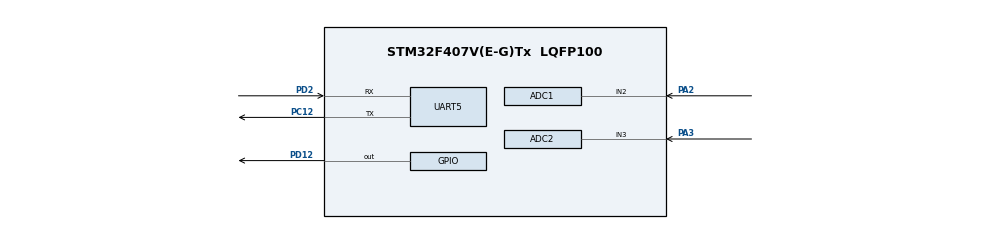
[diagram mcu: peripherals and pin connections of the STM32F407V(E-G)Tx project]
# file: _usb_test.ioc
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ADC1.Channel-8\#ChannelRegularConversion=ADC_CHANNEL_2
ADC1.ClockPrescaler=ADC_CLOCK_SYNC_PCLK_DIV8
ADC1.ContinuousConvMode=ENABLE
ADC1.DMAContinuousRequests=ENABLE
ADC1.EOCSelection=ADC_EOC_SINGLE_CONV
ADC1.Mode=ADC_DUALMODE_REGSIMULT
ADC1.NbrOfConversionFlag=1
ADC1.Rank-8\#ChannelRegularConversion=1
ADC1.SamplingTime-8\#ChannelRegularConversion=ADC_SAMPLETIME_3CYCLES
ADC1.master=1
ADC2.Channel-1\#ChannelRegularConversion=ADC_CHANNEL_3
ADC2.ClockPrescaler=ADC_CLOCK_SYNC_PCLK_DIV8
ADC2.DMAAccessMode=ADC_DMAACCESSMODE_2
ADC2.Mode=ADC_DUALMODE_REGSIMULT
ADC2.NbrOfConversionFlag=1
ADC2.Rank-1\#ChannelRegularConversion=1
ADC2.SamplingTime-1\#ChannelRegularConversion=ADC_SAMPLETIME_3CYCLES
Dma.ADC1.0.Direction=DMA_PERIPH_TO_MEMORY
Dma.ADC1.0.FIFOMode=DMA_FIFOMODE_DISABLE
Dma.ADC1.0.Instance=DMA2_Stream0
Dma.ADC1.0.MemDataAlignment=DMA_MDATAALIGN_WORD
Dma.ADC1.0.MemInc=DMA_MINC_ENABLE
Dma.ADC1.0.Mode=DMA_CIRCULAR
Dma.ADC1.0.PeriphDataAlignment=DMA_PDATAALIGN_WORD
Dma.ADC1.0.PeriphInc=DMA_PINC_DISABLE
Dma.ADC1.0.Priority=DMA_PRIORITY_LOW
Dma.Request0=ADC1
Mcu.Family=STM32F4
Mcu.Name=STM32F407V(E-G)Tx
Mcu.Package=LQFP100
NVIC.DMA2_Stream0_IRQn=true\:0\:0\:false\:false\:true\:false\:true\:true
NVIC.PriorityGroup=NVIC_PRIORITYGROUP_0
PA2.Signal=ADCx_IN2
PA3.Signal=ADCx_IN3
PC12.Mode=Asynchronous
PC12.Signal=UART5_TX
PC14-OSC32_IN.Mode=LSE-External-Oscillator
PC14-OSC32_IN.Signal=RCC_OSC32_IN
PC15-OSC32_OUT.Mode=LSE-External-Oscillator
PC15-OSC32_OUT.Signal=RCC_OSC32_OUT
PD12.GPIO_Speed=GPIO_SPEED_FREQ_VERY_HIGH
PD12.Signal=GPIO_Output
PD2.Mode=Asynchronous
PD2.Signal=UART5_RX
PH0-OSC_IN.Mode=HSE-External-Oscillator
PH0-OSC_IN.Signal=RCC_OSC_IN
PH1-OSC_OUT.Mode=HSE-External-Oscillator
PH1-OSC_OUT.Signal=RCC_OSC_OUT
ProjectManager.HeapSize=0x200
ProjectManager.StackSize=0x400
ProjectManager.TargetToolchain=STM32CubeIDE
RCC.48MHZClocksFreq_Value=96000000
RCC.AHBFreq_Value=336000000
RCC.APB1CLKDivider=RCC_HCLK_DIV4
RCC.APB1Freq_Value=84000000
RCC.APB1TimFreq_Value=168000000
RCC.APB2CLKDivider=RCC_HCLK_DIV2
RCC.APB2Freq_Value=168000000
RCC.APB2TimFreq_Value=336000000
RCC.CortexFreq_Value=336000000
RCC.HCLKFreq_Value=336000000
RCC.HSE_VALUE=8000000
RCC.HSI_VALUE=16000000
RCC.PLLM=2
RCC.PLLN=168
RCC.PLLQ=7
RCC.PLLSourceVirtual=RCC_PLLSOURCE_HSE
RCC.SYSCLKFreq_VALUE=336000000
RCC.SYSCLKSource=RCC_SYSCLKSOURCE_PLLCLK
RCC.VCOOutputFreq_Value=672000000
SH.ADCx_IN2.0=ADC1_IN2,IN2
SH.ADCx_IN3.0=ADC2_IN3,IN3
TIM2.Period=0xFFFFFFFF
TIM2.Prescaler=167
UART5.VirtualMode=Asynchronous
VP_TIM2_VS_OPM.Mode=OPM_bit
board=STM32F407G-DISC1

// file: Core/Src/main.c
/* USER CODE BEGIN Header */
/**
  ******************************************************************************
  * @file           : main.c
  * @brief          : Main program body
  ******************************************************************************
  * @attention
  *
  * Copyright (c) 2025 STMicroelectronics.
  * All rights reserved.
  *
  * This software is licensed under terms that can be found in the LICENSE file
  * in the root directory of this software component.
  * If no LICENSE file comes with this software, it is provided AS-IS.
  *
  ******************************************************************************
  */
/* USER CODE END Header */
#include "main.h"

/* USER CODE BEGIN Includes */
#include <stdio.h>
#include <string.h>
uint8_t mode,mode_ex;
uint8_t rxdata;
uint8_t completed=0;
/* USER CODE END Includes */

ADC_HandleTypeDef hadc1;
ADC_HandleTypeDef hadc2;
DMA_HandleTypeDef hdma_adc1;

TIM_HandleTypeDef htim2;

UART_HandleTypeDef huart5;

/* USER CODE BEGIN PV */
char buffer_cokomel[3]="ABC";
uint16_t adc_buffer_1[4096],adc_buffer_2[4096];
uint16_t adc_buffer[4096];
uint32_t adc_buffer_ex[4096];
void HAL_ADC_ConvHalfCpltCallback(ADC_HandleTypeDef* hadc){

}

void HAL_ADC_ConvCpltCallback(ADC_HandleTypeDef *hadc){
	//uint16_t ts_cal1=*TEMPSENSOR_CAL1_ADDR;
	//uint16_t ts_cal2=*TEMPSENSOR_CAL2_ADDR;
	//float temperature = ((float)(110-30)/(ts_cal2-ts_cal1)) * (adc_buffer[0] - ts_cal1)  + 30;
	HAL_GPIO_TogglePin(GPIOD, GPIO_PIN_12);
	//HAL_UART_Transmit(&huart4, buffer_cokomel,3,100);
	//HAL_ADC_Stop_DMA(&hadc2);
	//CDC_Transmit_FS(adc_buffer,sizeof(adc_buffer));
	//sprintf(buffer_cokomel, "%d", temperature);
	// do stuff with result
	//HAL_UART_Transmit(&huart4, buffer_cokomel,3,100);

//

}
/* USER CODE END PV */

void SystemClock_Config(void);
static void MX_GPIO_Init(void);
static void MX_DMA_Init(void);
static void MX_ADC1_Init(void);
static void MX_TIM2_Init(void);
static void MX_ADC2_Init(void);
static void MX_UART5_Init(void);

int main(void)
{

  /* MCU Configuration--------------------------------------------------------*/

  /* Reset of all peripherals, Initializes the Flash interface and the Systick. */
  HAL_Init();

  /* Configure the system clock */
  SystemClock_Config();

  /* Initialize all configured peripherals */
  MX_GPIO_Init();
  MX_DMA_Init();
  MX_ADC1_Init();
  MX_TIM2_Init();
  MX_ADC2_Init();
  MX_UART5_Init();

  /* Infinite loop */
  /* USER CODE BEGIN WHILE */
  //HAL_ADC_Start_DMA(&hadc1,(uint32_t *)adc_buffer,sizeof(adc_buffer));
  HAL_ADC_Start(&hadc2);
  HAL_ADCEx_MultiModeStart_DMA(&hadc1, adc_buffer_ex, sizeof(adc_buffer_ex));

   while (1)
  {
	  HAL_UART_Receive(&huart5, &rxdata,1,1);
	  if(rxdata=='a'){
		  HAL_ADC_Stop(&hadc2);
		  HAL_ADCEx_MultiModeStop_DMA(&hadc1);
			  if(HAL_UART_Transmit(&huart5, adc_buffer_ex,sizeof(adc_buffer_ex),2000)!=HAL_OK)
			  HAL_UART_Transmit(&huart5, buffer_cokomel,3,100);
		  rxdata='\0';
		  HAL_ADC_Start(&hadc2);
		  HAL_ADCEx_MultiModeStart_DMA(&hadc1, adc_buffer_ex, sizeof(adc_buffer_ex));

		//  HAL_ADC_Start_DMA(&hadc1,(uint32_t *)adc_buffer,sizeof(adc_buffer));
		  completed=0;
		/*  HAL_ADC_Start(&hadc2);
		  HAL_ADCEx_MultiModeStart_DMA(&hadc1,(uint32_t *)adc_buffer,sizeof(adc_buffer));
		//  HAL_ADC_Start_DMA(&hadc2,(uint32_t *)&adc_buffer[4096],8192);
		  rxdata='\0';
		  HAL_Delay(100);
		  HAL_ADCEx_MultiModeStop_DMA(&hadc1);
		  HAL_ADC_Stop(&hadc2);
		  //HAL_ADC_Stop_DMA(&hadc2);
		  CDC_Transmit_FS(adc_buffer,sizeof(adc_buffer));
		 // CDC_Transmit_FS(adc_buffer_2,sizeof(adc_buffer_2));
*/
	  }

	//  HAL_Delay(1);

    /* USER CODE END WHILE */

  }
}

void SystemClock_Config1(void)
{
  RCC_OscInitTypeDef RCC_OscInitStruct = {0};
  RCC_ClkInitTypeDef RCC_ClkInitStruct = {0};

  /** Configure the main internal regulator output voltage
  */
  __HAL_RCC_PWR_CLK_ENABLE();
  __HAL_PWR_VOLTAGESCALING_CONFIG(PWR_REGULATOR_VOLTAGE_SCALE1);

  /** Initializes the RCC Oscillators according to the specified parameters
  * in the RCC_OscInitTypeDef structure.
  */
  RCC_OscInitStruct.OscillatorType = RCC_OSCILLATORTYPE_HSE;
  RCC_OscInitStruct.HSEState = RCC_HSE_ON;
  RCC_OscInitStruct.PLL.PLLState = RCC_PLL_ON;
  RCC_OscInitStruct.PLL.PLLSource = RCC_PLLSOURCE_HSE;
  RCC_OscInitStruct.PLL.PLLM = 4;
  RCC_OscInitStruct.PLL.PLLN = 180;
  RCC_OscInitStruct.PLL.PLLP = RCC_PLLP_DIV2;
  RCC_OscInitStruct.PLL.PLLQ = 7;
  if (HAL_RCC_OscConfig(&RCC_OscInitStruct) != HAL_OK)
  {
    Error_Handler();
  }

  /** Initializes the CPU, AHB and APB buses clocks
  */
  RCC_ClkInitStruct.ClockType = RCC_CLOCKTYPE_HCLK|RCC_CLOCKTYPE_SYSCLK
                              |RCC_CLOCKTYPE_PCLK1|RCC_CLOCKTYPE_PCLK2;
  RCC_ClkInitStruct.SYSCLKSource = RCC_SYSCLKSOURCE_PLLCLK;
  RCC_ClkInitStruct.AHBCLKDivider = RCC_SYSCLK_DIV1;
  RCC_ClkInitStruct.APB1CLKDivider = RCC_HCLK_DIV16;
  RCC_ClkInitStruct.APB2CLKDivider = RCC_HCLK_DIV1;

  if (HAL_RCC_ClockConfig(&RCC_ClkInitStruct, FLASH_LATENCY_5) != HAL_OK)
  {
    Error_Handler();
  }
}
void SystemClock_Config(void)
{
  RCC_OscInitTypeDef RCC_OscInitStruct = {0};
  RCC_ClkInitTypeDef RCC_ClkInitStruct = {0};

  /** Configure the main internal regulator output voltage
  */
  __HAL_RCC_PWR_CLK_ENABLE();
  __HAL_PWR_VOLTAGESCALING_CONFIG(PWR_REGULATOR_VOLTAGE_SCALE1);

  /** Initializes the RCC Oscillators according to the specified parameters
  * in the RCC_OscInitTypeDef structure.
  */
  RCC_OscInitStruct.OscillatorType = RCC_OSCILLATORTYPE_HSE;
  RCC_OscInitStruct.HSEState = RCC_HSE_ON;
  RCC_OscInitStruct.PLL.PLLState = RCC_PLL_ON;
  RCC_OscInitStruct.PLL.PLLSource = RCC_PLLSOURCE_HSE;
  RCC_OscInitStruct.PLL.PLLM = 4;
  RCC_OscInitStruct.PLL.PLLN = 180;
  RCC_OscInitStruct.PLL.PLLP = RCC_PLLP_DIV2;
  RCC_OscInitStruct.PLL.PLLQ = 7;
  if (HAL_RCC_OscConfig(&RCC_OscInitStruct) != HAL_OK)
  {
    Error_Handler();
  }

  /** Initializes the CPU, AHB and APB buses clocks
  */
  RCC_ClkInitStruct.ClockType = RCC_CLOCKTYPE_HCLK|RCC_CLOCKTYPE_SYSCLK
                              |RCC_CLOCKTYPE_PCLK1|RCC_CLOCKTYPE_PCLK2;
  RCC_ClkInitStruct.SYSCLKSource = RCC_SYSCLKSOURCE_PLLCLK;
  RCC_ClkInitStruct.AHBCLKDivider = RCC_SYSCLK_DIV1;
  RCC_ClkInitStruct.APB1CLKDivider = RCC_HCLK_DIV16;
  RCC_ClkInitStruct.APB2CLKDivider = RCC_HCLK_DIV1;

  if (HAL_RCC_ClockConfig(&RCC_ClkInitStruct, FLASH_LATENCY_5) != HAL_OK)
  {
    Error_Handler();
  }
}

static void MX_ADC1_Init(void)
{

  ADC_MultiModeTypeDef multimode = {0};
  ADC_ChannelConfTypeDef sConfig = {0};

  /** Configure the global features of the ADC (Clock, Resolution, Data Alignment and number of conversion)
  */
  hadc1.Instance = ADC1;
  hadc1.Init.ClockPrescaler = ADC_CLOCK_SYNC_PCLK_DIV2;
  hadc1.Init.Resolution = ADC_RESOLUTION_12B;
  hadc1.Init.ScanConvMode = DISABLE;
  hadc1.Init.ContinuousConvMode = ENABLE;
  hadc1.Init.DiscontinuousConvMode = DISABLE;
  hadc1.Init.ExternalTrigConvEdge = ADC_EXTERNALTRIGCONVEDGE_NONE;
  hadc1.Init.ExternalTrigConv = ADC_SOFTWARE_START;
  hadc1.Init.DataAlign = ADC_DATAALIGN_RIGHT;
  hadc1.Init.NbrOfConversion = 1;
  hadc1.Init.DMAContinuousRequests = ENABLE;
  hadc1.Init.EOCSelection = ADC_EOC_SINGLE_CONV;
  if (HAL_ADC_Init(&hadc1) != HAL_OK)
  {
    Error_Handler();
  }

  /** Configure the ADC multi-mode
  */
  multimode.Mode = ADC_DUALMODE_REGSIMULT;
  multimode.DMAAccessMode = ADC_DMAACCESSMODE_2;
  multimode.TwoSamplingDelay = ADC_TWOSAMPLINGDELAY_5CYCLES;
  if (HAL_ADCEx_MultiModeConfigChannel(&hadc1, &multimode) != HAL_OK)
  {
    Error_Handler();
  }

  /** Configure for the selected ADC regular channel its corresponding rank in the sequencer and its sample time.
  */
  sConfig.Channel = ADC_CHANNEL_2;
  sConfig.Rank = 1;
  sConfig.SamplingTime = 1.5;//ADC_SAMPLETIME_3CYCLES;
  if (HAL_ADC_ConfigChannel(&hadc1, &sConfig) != HAL_OK)
  {
    Error_Handler();
  }

}

static void MX_ADC2_Init(void)
{

  ADC_ChannelConfTypeDef sConfig = {0};

  /** Configure the global features of the ADC (Clock, Resolution, Data Alignment and number of conversion)
  */
  hadc2.Instance = ADC2;
  hadc2.Init.ClockPrescaler = ADC_CLOCK_SYNC_PCLK_DIV2;
  hadc2.Init.Resolution = ADC_RESOLUTION_12B;
  hadc2.Init.ScanConvMode = DISABLE;
  hadc2.Init.ContinuousConvMode = ENABLE;
  hadc2.Init.DiscontinuousConvMode = DISABLE;
  hadc2.Init.DataAlign = ADC_DATAALIGN_RIGHT;
  hadc2.Init.NbrOfConversion = 1;
  hadc2.Init.DMAContinuousRequests = DISABLE;
  hadc2.Init.ExternalTrigConvEdge = ADC_EXTERNALTRIGCONVEDGE_NONE;
  hadc2.Init.ExternalTrigConv = ADC_SOFTWARE_START;
  hadc2.Init.EOCSelection = ADC_EOC_SINGLE_CONV;
  if (HAL_ADC_Init(&hadc2) != HAL_OK)
  {
    Error_Handler();
  }

  /** Configure for the selected ADC regular channel its corresponding rank in the sequencer and its sample time.
  */
  sConfig.Channel = ADC_CHANNEL_3;
  sConfig.Rank = 1;
  sConfig.SamplingTime = 1.5;//ADC_SAMPLETIME_3CYCLES;
  if (HAL_ADC_ConfigChannel(&hadc2, &sConfig) != HAL_OK)
  {
    Error_Handler();
  }

}

static void MX_TIM2_Init(void)
{

  TIM_MasterConfigTypeDef sMasterConfig = {0};

  htim2.Instance = TIM2;
  htim2.Init.Prescaler = 167;
  htim2.Init.CounterMode = TIM_COUNTERMODE_UP;
  htim2.Init.Period = 0xFFFFFFFF;
  htim2.Init.ClockDivision = TIM_CLOCKDIVISION_DIV1;
  htim2.Init.AutoReloadPreload = TIM_AUTORELOAD_PRELOAD_DISABLE;
  if (HAL_TIM_OnePulse_Init(&htim2, TIM_OPMODE_SINGLE) != HAL_OK)
  {
    Error_Handler();
  }
  sMasterConfig.MasterOutputTrigger = TIM_TRGO_RESET;
  sMasterConfig.MasterSlaveMode = TIM_MASTERSLAVEMODE_DISABLE;
  if (HAL_TIMEx_MasterConfigSynchronization(&htim2, &sMasterConfig) != HAL_OK)
  {
    Error_Handler();
  }

}

static void MX_UART5_Init(void)
{

  huart5.Instance = UART5;
  huart5.Init.BaudRate = 115200;
  huart5.Init.WordLength = UART_WORDLENGTH_8B;
  huart5.Init.StopBits = UART_STOPBITS_1;
  huart5.Init.Parity = UART_PARITY_NONE;
  huart5.Init.Mode = UART_MODE_TX_RX;
  huart5.Init.HwFlowCtl = UART_HWCONTROL_NONE;
  huart5.Init.OverSampling = UART_OVERSAMPLING_16;
  if (HAL_UART_Init(&huart5) != HAL_OK)
  {
    Error_Handler();
  }

}

static void MX_DMA_Init(void)
{

  /* DMA controller clock enable */
  __HAL_RCC_DMA2_CLK_ENABLE();

  /* DMA interrupt init */
  /* DMA2_Stream0_IRQn interrupt configuration */
  HAL_NVIC_SetPriority(DMA2_Stream0_IRQn, 0, 0);
  HAL_NVIC_EnableIRQ(DMA2_Stream0_IRQn);

}

static void MX_GPIO_Init(void)
{
  GPIO_InitTypeDef GPIO_InitStruct = {0};

  /* GPIO Ports Clock Enable */
  __HAL_RCC_GPIOC_CLK_ENABLE();
  __HAL_RCC_GPIOH_CLK_ENABLE();
  __HAL_RCC_GPIOA_CLK_ENABLE();
  __HAL_RCC_GPIOD_CLK_ENABLE();

  /*Configure GPIO pin Output Level */
  HAL_GPIO_WritePin(GPIOD, GPIO_PIN_12, GPIO_PIN_RESET);

  /*Configure GPIO pin : PD12 */
  GPIO_InitStruct.Pin = GPIO_PIN_12;
  GPIO_InitStruct.Mode = GPIO_MODE_OUTPUT_PP;
  GPIO_InitStruct.Pull = GPIO_NOPULL;
  GPIO_InitStruct.Speed = GPIO_SPEED_FREQ_VERY_HIGH;
  HAL_GPIO_Init(GPIOD, &GPIO_InitStruct);

}

void Error_Handler(void)
{
  __disable_irq();
  while (1)
  {
  }
}
